One B-rep face of a CAD part: STEP entity #480.
In plain terms, the planar face has unit normal (1, 0, 0).
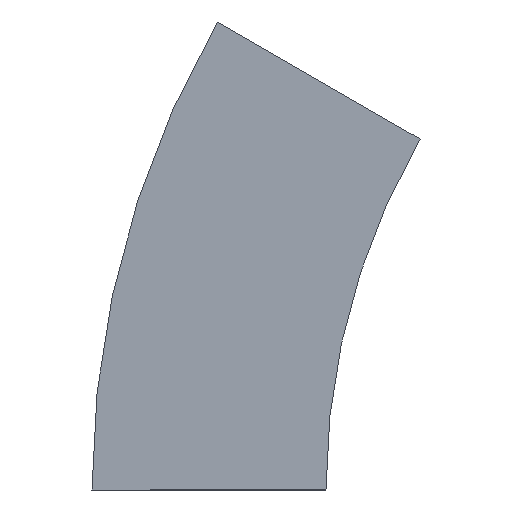
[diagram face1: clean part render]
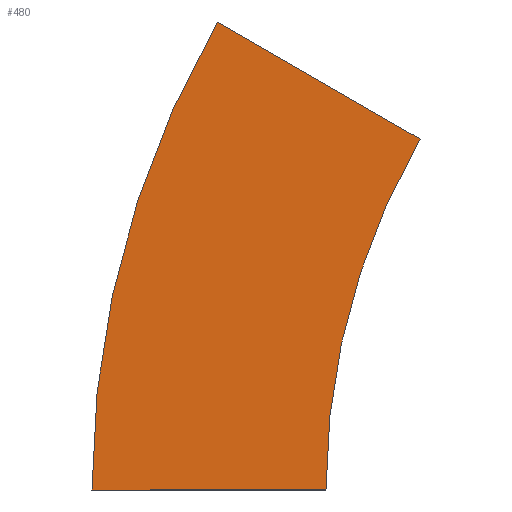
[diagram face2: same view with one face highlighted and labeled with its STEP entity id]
Its self-contained STEP definition (entity closure, numbers rounded to 3 decimals):
#8 = PLANE ( 'NONE',  #402 ) ;
#10 = CARTESIAN_POINT ( 'NONE',  ( 0., 100., 0. ) ) ;
#27 = EDGE_CURVE ( 'NONE', #272, #105, #519, .T. ) ;
#31 = EDGE_LOOP ( 'NONE', ( #234, #190, #494, #92 ) ) ;
#42 = CARTESIAN_POINT ( 'NONE',  ( 0., -40.192, 150. ) ) ;
#44 = CARTESIAN_POINT ( 'NONE',  ( 0., 0., 0. ) ) ;
#49 = VECTOR ( 'NONE', #297, 1000. ) ;
#56 = DIRECTION ( 'NONE',  ( 0., 1., 0. ) ) ;
#60 = DIRECTION ( 'NONE',  ( 0., 1., 0. ) ) ;
#73 = CIRCLE ( 'NONE', #504, 300. ) ;
#87 = VERTEX_POINT ( 'NONE', #256 ) ;
#92 = ORIENTED_EDGE ( 'NONE', *, *, #343, .T. ) ;
#97 = CIRCLE ( 'NONE', #425, 400. ) ;
#99 = LINE ( 'NONE', #44, #252 ) ;
#104 = DIRECTION ( 'NONE',  ( 0., 0., -1. ) ) ;
#105 = VERTEX_POINT ( 'NONE', #478 ) ;
#168 = VERTEX_POINT ( 'NONE', #10 ) ;
#190 = ORIENTED_EDGE ( 'NONE', *, *, #27, .F. ) ;
#234 = ORIENTED_EDGE ( 'NONE', *, *, #454, .T. ) ;
#252 = VECTOR ( 'NONE', #56, 1000. ) ;
#256 = CARTESIAN_POINT ( 'NONE',  ( 0., 0., 0. ) ) ;
#272 = VERTEX_POINT ( 'NONE', #42 ) ;
#284 = FACE_OUTER_BOUND ( 'NONE', #31, .T. ) ;
#287 = DIRECTION ( 'NONE',  ( 1., 0., 0. ) ) ;
#297 = DIRECTION ( 'NONE',  ( 0., 0.866, 0.5 ) ) ;
#343 = EDGE_CURVE ( 'NONE', #87, #168, #99, .T. ) ;
#366 = CARTESIAN_POINT ( 'NONE',  ( 0., -300., 0. ) ) ;
#369 = CARTESIAN_POINT ( 'NONE',  ( 0., -40.192, 150. ) ) ;
#393 = EDGE_CURVE ( 'NONE', #87, #272, #73, .T. ) ;
#402 = AXIS2_PLACEMENT_3D ( 'NONE', #407, #508, #104 ) ;
#403 = DIRECTION ( 'NONE',  ( 1., 0., 0. ) ) ;
#407 = CARTESIAN_POINT ( 'NONE',  ( 0., 0., 0. ) ) ;
#425 = AXIS2_PLACEMENT_3D ( 'NONE', #459, #287, #60 ) ;
#454 = EDGE_CURVE ( 'NONE', #168, #105, #97, .T. ) ;
#459 = CARTESIAN_POINT ( 'NONE',  ( 0., -300., 0. ) ) ;
#478 = CARTESIAN_POINT ( 'NONE',  ( 0., 46.41, 200. ) ) ;
#480 = ADVANCED_FACE ( 'NONE', ( #284 ), #8, .T. ) ;
#494 = ORIENTED_EDGE ( 'NONE', *, *, #393, .F. ) ;
#504 = AXIS2_PLACEMENT_3D ( 'NONE', #366, #403, #507 ) ;
#507 = DIRECTION ( 'NONE',  ( 0., 1., 0. ) ) ;
#508 = DIRECTION ( 'NONE',  ( 1., 0., 0. ) ) ;
#519 = LINE ( 'NONE', #369, #49 ) ;
